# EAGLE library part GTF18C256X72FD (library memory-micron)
2GB (x72, DR) 240-Pin DDR2 SDRAM FBDIMM 1.5V DDR2 SDRAM FBDIMM, MT18GTF25672FDY - 2GB Source: Micron Technology , GTF18C256x72FD.pdf Auto generated by make-symbol-device-package-bsdl.ulp Rev. 20

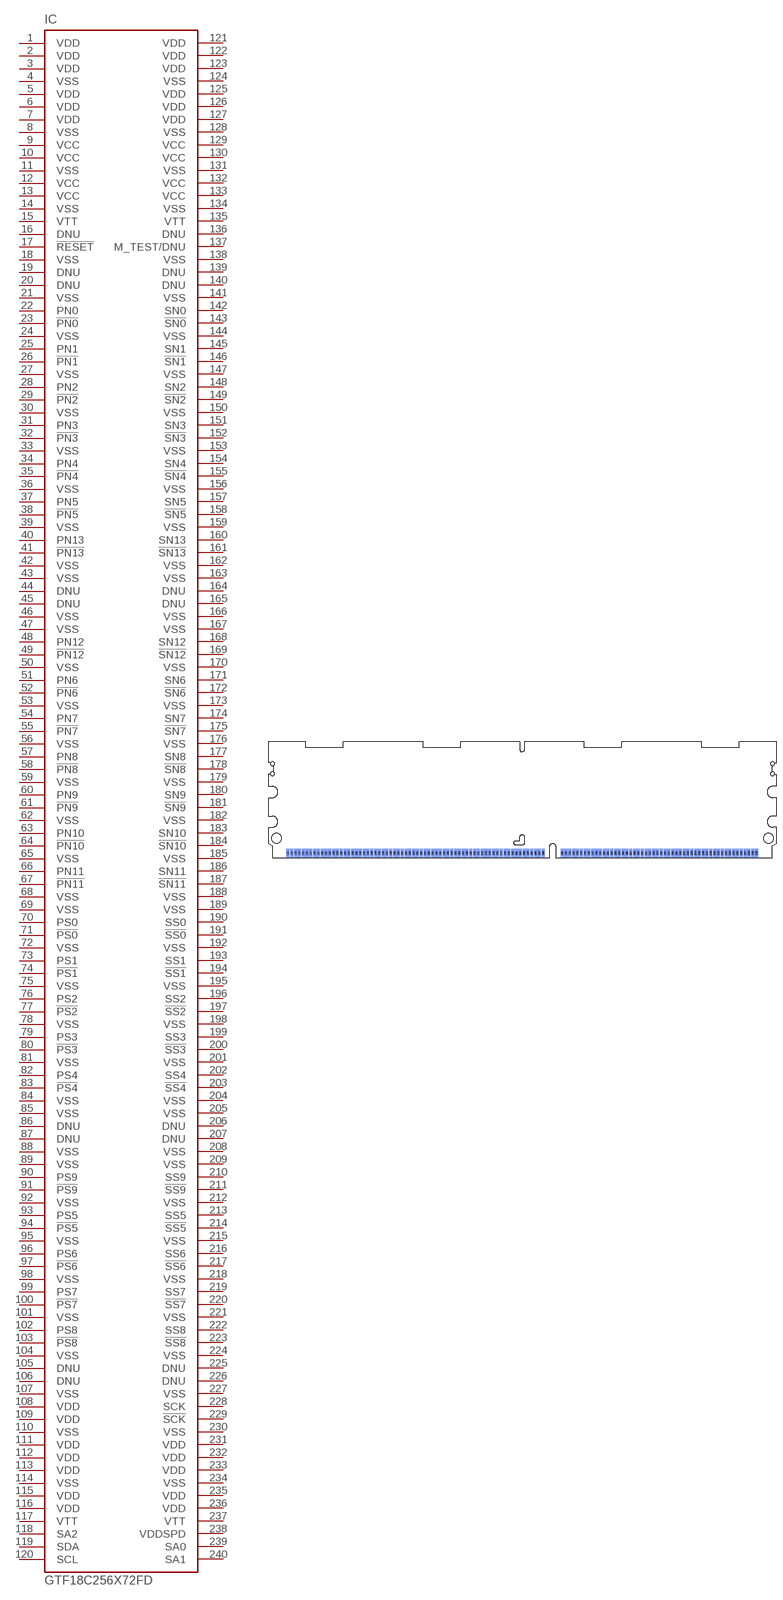
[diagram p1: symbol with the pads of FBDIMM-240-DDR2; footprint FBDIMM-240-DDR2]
Designator prefix IC

## GTF18C256X72FDDIMII-240 (OC_FARNELL: unknown; OC_NEWARK: unknown)  [FBDIMM-240-DDR2]
1  VDD  pas
2  VDD  pas
3  VDD  pas
4  VSS  pas
5  VDD  pas
6  VDD  pas
7  VDD  pas
8  VSS  pas
9  VCC  pas
10  VCC  pas
11  VSS  pas
12  VCC  pas
13  VCC  pas
14  VSS  pas
15  VTT  pas
16  DNU  pas
17  !RESET  pas
18  VSS  pas
19  DNU  pas
20  DNU  pas
21  VSS  pas
22  PN0  pas
23  !PN0  pas
24  VSS  pas
25  PN1  pas
26  !PN1  pas
27  VSS  pas
28  PN2  pas
29  !PN2  pas
30  VSS  pas
31  PN3  pas
32  !PN3  pas
33  VSS  pas
34  PN4  pas
35  !PN4  pas
36  VSS  pas
37  PN5  pas
38  !PN5  pas
39  VSS  pas
40  PN13  pas
41  !PN13  pas
42  VSS  pas
43  VSS  pas
44  DNU  pas
45  DNU  pas
46  VSS  pas
47  VSS  pas
48  PN12  pas
49  !PN12  pas
50  VSS  pas
51  PN6  pas
52  !PN6  pas
53  VSS  pas
54  PN7  pas
55  !PN7  pas
56  VSS  pas
57  PN8  pas
58  !PN8  pas
59  VSS  pas
60  PN9  pas
61  !PN9  pas
62  VSS  pas
63  PN10  pas
64  !PN10  pas
65  VSS  pas
66  PN11  pas
67  !PN11  pas
68  VSS  pas
69  VSS  pas
70  PS0  pas
71  !PS0  pas
72  VSS  pas
73  PS1  pas
74  !PS1  pas
75  VSS  pas
76  PS2  pas
77  !PS2  pas
78  VSS  pas
79  PS3  pas
80  !PS3  pas
81  VSS  pas
82  PS4  pas
83  !PS4  pas
84  VSS  pas
85  VSS  pas
86  DNU  pas
87  DNU  pas
88  VSS  pas
89  VSS  pas
90  PS9  pas
91  !PS9  pas
92  VSS  pas
93  PS5  pas
94  !PS5  pas
95  VSS  pas
96  PS6  pas
97  !PS6  pas
98  VSS  pas
99  PS7  pas
100  !PS7  pas
101  VSS  pas
102  PS8  pas
103  !PS8  pas
104  VSS  pas
105  DNU  pas
106  DNU  pas
107  VSS  pas
108  VDD  pas
109  VDD  pas
110  VSS  pas
111  VDD  pas
112  VDD  pas
113  VDD  pas
114  VSS  pas
115  VDD  pas
116  VDD  pas
117  VTT  pas
118  SA2  pas
119  SDA  pas
120  SCL  pas
121  VDD  pas
122  VDD  pas
123  VDD  pas
124  VSS  pas
125  VDD  pas
126  VDD  pas
127  VDD  pas
128  VSS  pas
129  VCC  pas
130  VCC  pas
131  VSS  pas
132  VCC  pas
133  VCC  pas
134  VSS  pas
135  VTT  pas
136  DNU  pas
137  M_TEST/DNU  pas
138  VSS  pas
139  DNU  pas
140  DNU  pas
141  VSS  pas
142  SN0  pas
143  !SN0  pas
144  VSS  pas
145  SN1  pas
146  !SN1  pas
147  VSS  pas
148  SN2  pas
149  !SN2  pas
150  VSS  pas
151  SN3  pas
152  !SN3  pas
153  VSS  pas
154  SN4  pas
155  !SN4  pas
156  VSS  pas
157  SN5  pas
158  !SN5  pas
159  VSS  pas
160  SN13  pas
161  !SN13  pas
162  VSS  pas
163  VSS  pas
164  DNU  pas
165  DNU  pas
166  VSS  pas
167  VSS  pas
168  SN12  pas
169  !SN12  pas
170  VSS  pas
171  SN6  pas
172  !SN6  pas
173  VSS  pas
174  SN7  pas
175  !SN7  pas
176  VSS  pas
177  SN8  pas
178  !SN8  pas
179  VSS  pas
180  SN9  pas
181  !SN9  pas
182  VSS  pas
183  SN10  pas
184  !SN10  pas
185  VSS  pas
186  SN11  pas
187  !SN11  pas
188  VSS  pas
189  VSS  pas
190  SS0  pas
191  !SS0  pas
192  VSS  pas
193  SS1  pas
194  !SS1  pas
195  VSS  pas
196  SS2  pas
197  !SS2  pas
198  VSS  pas
199  SS3  pas
200  !SS3  pas
201  VSS  pas
202  SS4  pas
203  !SS4  pas
204  VSS  pas
205  VSS  pas
206  DNU  pas
207  DNU  pas
208  VSS  pas
209  VSS  pas
210  SS9  pas
211  !SS9  pas
212  VSS  pas
213  SS5  pas
214  !SS5  pas
215  VSS  pas
216  SS6  pas
217  !SS6  pas
218  VSS  pas
219  SS7  pas
220  !SS7  pas
221  VSS  pas
222  SS8  pas
223  !SS8  pas
224  VSS  pas
225  DNU  pas
226  DNU  pas
227  VSS  pas
228  SCK  pas
229  !SCK  pas
230  VSS  pas
231  VDD  pas
232  VDD  pas
233  VDD  pas
234  VSS  pas
235  VDD  pas
236  VDD  pas
237  VTT  pas
238  VDDSPD  pas
239  SA0  pas
240  SA1  pas

## Footprint FBDIMM-240-DDR2 (pad centres in mm)
240-Pin DDR2 SDRAM FBDIMM (MO-256 R/C B) Source: www.micron.com .. GTF18C256x72FD.pdf
smd 0.8 x 2.3: 1 -69.5,1.25; 2 -68.5,1.25; 3 -67.5,1.25; 4 -66.5,1.25; 5 -65.5,1.25; 6 -64.5,1.25; 7 -63.5,1.25; 8 -62.5,1.25; 9 -61.5,1.25; 10 -60.5,1.25; 11 -59.5,1.25; 12 -58.5,1.25; 13 -57.5,1.25; 14 -56.5,1.25; 15 -55.5,1.25; 16 -54.5,1.25; 17 -53.5,1.25; 18 -52.5,1.25; 19 -51.5,1.25; 20 -50.5,1.25; 21 -49.5,1.25; 22 -48.5,1.25; 23 -47.5,1.25; 24 -46.5,1.25; 25 -45.5,1.25; 26 -44.5,1.25; 27 -43.5,1.25; 28 -42.5,1.25; 29 -41.5,1.25; 30 -40.5,1.25; 31 -39.5,1.25; 32 -38.5,1.25; 33 -37.5,1.25; 34 -36.5,1.25; 35 -35.5,1.25; 36 -34.5,1.25; 37 -33.5,1.25; 38 -32.5,1.25; 39 -31.5,1.25; 40 -30.5,1.25; 41 -29.5,1.25; 42 -28.5,1.25; 43 -27.5,1.25; 44 -26.5,1.25; 45 -25.5,1.25; 46 -24.5,1.25; 47 -23.5,1.25; 48 -22.5,1.25; 49 -21.5,1.25; 50 -20.5,1.25; 51 -19.5,1.25; 52 -18.5,1.25; 53 -17.5,1.25; 54 -16.5,1.25; 55 -15.5,1.25; 56 -14.5,1.25; 57 -13.5,1.25; 58 -12.5,1.25; 59 -11.5,1.25; 60 -10.5,1.25; 61 -9.5,1.25; 62 -8.5,1.25; 63 -7.5,1.25; 64 -6.5,1.25; 65 -5.5,1.25; 66 -4.5,1.25; 67 -3.5,1.25; 68 -2.5,1.25; 69 2.5,1.25; 70 3.5,1.25; 71 4.5,1.25; 72 5.5,1.25; 73 6.5,1.25; 74 7.5,1.25; 75 8.5,1.25; 76 9.5,1.25; 77 10.5,1.25; 78 11.5,1.25; 79 12.5,1.25; 80 13.5,1.25; 81 14.5,1.25; 82 15.5,1.25; 83 16.5,1.25; 84 17.5,1.25; 85 18.5,1.25; 86 19.5,1.25; 87 20.5,1.25; 88 21.5,1.25; 89 22.5,1.25; 90 23.5,1.25; 91 24.5,1.25; 92 25.5,1.25; 93 26.5,1.25; 94 27.5,1.25; 95 28.5,1.25; 96 29.5,1.25; 97 30.5,1.25; 98 31.5,1.25; 99 32.5,1.25; 100 33.5,1.25; 101 34.5,1.25; 102 35.5,1.25; 103 36.5,1.25; 104 37.5,1.25; 105 38.5,1.25; 106 39.5,1.25; 107 40.5,1.25; 108 41.5,1.25; 109 42.5,1.25; 110 43.5,1.25; 111 44.5,1.25; 112 45.5,1.25; 113 46.5,1.25; 114 47.5,1.25; 115 48.5,1.25; 116 49.5,1.25; 117 50.5,1.25; 118 51.5,1.25; 119 52.5,1.25; 120 53.5,1.25
smd 0.8 x 2.3 bottom: 121 -69.5,1.25; 122 -68.5,1.25; 123 -67.5,1.25; 124 -66.5,1.25; 125 -65.5,1.25; 126 -64.5,1.25; 127 -63.5,1.25; 128 -62.5,1.25; 129 -61.5,1.25; 130 -60.5,1.25; 131 -59.5,1.25; 132 -58.5,1.25; 133 -57.5,1.25; 134 -56.5,1.25; 135 -55.5,1.25; 136 -54.5,1.25; 137 -53.5,1.25; 138 -52.5,1.25; 139 -51.5,1.25; 140 -50.5,1.25; 141 -49.5,1.25; 142 -48.5,1.25; 143 -47.5,1.25; 144 -46.5,1.25; 145 -45.5,1.25; 146 -44.5,1.25; 147 -43.5,1.25; 148 -42.5,1.25; 149 -41.5,1.25; 150 -40.5,1.25; 151 -39.5,1.25; 152 -38.5,1.25; 153 -37.5,1.25; 154 -36.5,1.25; 155 -35.5,1.25; 156 -34.5,1.25; 157 -33.5,1.25; 158 -32.5,1.25; 159 -31.5,1.25; 160 -30.5,1.25; 161 -29.5,1.25; 162 -28.5,1.25; 163 -27.5,1.25; 164 -26.5,1.25; 165 -25.5,1.25; 166 -24.5,1.25; 167 -23.5,1.25; 168 -22.5,1.25; 169 -21.5,1.25; 170 -20.5,1.25; 171 -19.5,1.25; 172 -18.5,1.25; 173 -17.5,1.25; 174 -16.5,1.25; 175 -15.5,1.25; 176 -14.5,1.25; 177 -13.5,1.25; 178 -12.5,1.25; 179 -11.5,1.25; 180 -10.5,1.25; 181 -9.5,1.25; 182 -8.5,1.25; 183 -7.5,1.25; 184 -6.5,1.25; 185 -5.5,1.25; 186 -4.5,1.25; 187 -3.5,1.25; 188 -2.5,1.25; 189 2.5,1.25; 190 3.5,1.25; 191 4.5,1.25; 192 5.5,1.25; 193 6.5,1.25; 194 7.5,1.25; 195 8.5,1.25; 196 9.5,1.25; 197 10.5,1.25; 198 11.5,1.25; 199 12.5,1.25; 200 13.5,1.25; 201 14.5,1.25; 202 15.5,1.25; 203 16.5,1.25; 204 17.5,1.25; 205 18.5,1.25; 206 19.5,1.25; 207 20.5,1.25; 208 21.5,1.25; 209 22.5,1.25; 210 23.5,1.25; 211 24.5,1.25; 212 25.5,1.25; 213 26.5,1.25; 214 27.5,1.25; 215 28.5,1.25; 216 29.5,1.25; 217 30.5,1.25; 218 31.5,1.25; 219 32.5,1.25; 220 33.5,1.25; 221 34.5,1.25; 222 35.5,1.25; 223 36.5,1.25; 224 37.5,1.25; 225 38.5,1.25; 226 39.5,1.25; 227 40.5,1.25; 228 41.5,1.25; 229 42.5,1.25; 230 43.5,1.25; 231 44.5,1.25; 232 45.5,1.25; 233 46.5,1.25; 234 47.5,1.25; 235 48.5,1.25; 236 49.5,1.25; 237 50.5,1.25; 238 51.5,1.25; 239 52.5,1.25; 240 53.5,1.25
hole 2.6 at -72.495,5.2
hole 2.6 at 56.645,5.2
hole 1 at -73.565,24.75
hole 1 at -73.57,22.075
hole 1 at 57.69,24.75
hole 1 at 57.695,22.075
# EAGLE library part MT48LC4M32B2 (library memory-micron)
SYNCHRONOUS DRAM 1 Meg x 32 x 4 banks Source: http://www.datasheetcatalog.org/datasheet/micron/MT48LC4M32B2.pdf

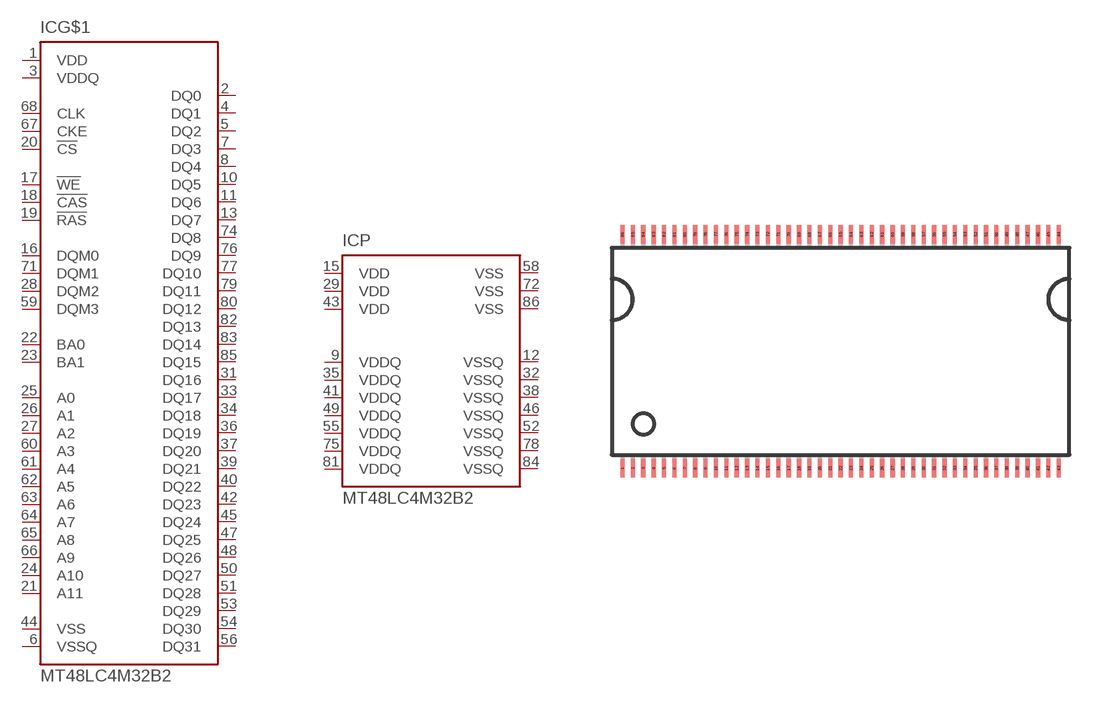
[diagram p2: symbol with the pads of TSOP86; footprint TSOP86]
Designator prefix IC; gates G$1=MT48LC4M32B2 P=MT48LC4M32B2-PWR

## MT48LC4M32B2 (MPN: MT48LC4M32B2P-6:G; OC_FARNELL: 1216286; OC_NEWARK: 97K6124)  [TSOP86]
1  G$1:VDD  pwr
2  G$1:DQ0  in
3  G$1:VDDQ  pwr
4  G$1:DQ1  in
5  G$1:DQ2  in
6  G$1:VSSQ  pwr
7  G$1:DQ3  in
8  G$1:DQ4  in
9  P:VDDQ  pwr
10  G$1:DQ5  in
11  G$1:DQ6  in
12  P:VSSQ  pwr
13  G$1:DQ7  in
15  P:VDD  pwr
16  G$1:DQM0  in
17  G$1:!WE  in
18  G$1:!CAS  in
19  G$1:!RAS  in
20  G$1:!CS  in
21  G$1:A11  in
22  G$1:BA0  in
23  G$1:BA1  in
24  G$1:A10  in
25  G$1:A0  in
26  G$1:A1  in
27  G$1:A2  in
28  G$1:DQM2  in
29  P:VDD  pwr
31  G$1:DQ16  in
32  P:VSSQ  pwr
33  G$1:DQ17  in
34  G$1:DQ18  in
35  P:VDDQ  pwr
36  G$1:DQ19  in
37  G$1:DQ20  in
38  P:VSSQ  pwr
39  G$1:DQ21  in
40  G$1:DQ22  in
41  P:VDDQ  pwr
42  G$1:DQ23  in
43  P:VDD  pwr
44  G$1:VSS  pwr
45  G$1:DQ24  in
46  P:VSSQ  pwr
47  G$1:DQ25  in
48  G$1:DQ26  in
49  P:VDDQ  pwr
50  G$1:DQ27  in
51  G$1:DQ28  in
52  P:VSSQ  pwr
53  G$1:DQ29  in
54  G$1:DQ30  in
55  P:VDDQ  pwr
56  G$1:DQ31  in
58  P:VSS  pwr
59  G$1:DQM3  in
60  G$1:A3  in
61  G$1:A4  in
62  G$1:A5  in
63  G$1:A6  in
64  G$1:A7  in
65  G$1:A8  in
66  G$1:A9  in
67  G$1:CKE  in
68  G$1:CLK  in
71  G$1:DQM1  in
72  P:VSS  pwr
74  G$1:DQ8  in
75  P:VDDQ  pwr
76  G$1:DQ9  in
77  G$1:DQ10  in
78  P:VSSQ  pwr
79  G$1:DQ11  in
80  G$1:DQ12  in
81  P:VDDQ  pwr
82  G$1:DQ13  in
83  G$1:DQ14  in
84  P:VSSQ  pwr
85  G$1:DQ15  in
86  P:VSS  pwr

## Footprint TSOP86 (pad centres in mm)
TSOP86 Auto generated by make-symbol-device-package-bsdl.ulp Rev. 26
smd 0.2 x 0.9: 1 -10.5,-5.63; 2 -10,-5.63; 3 -9.5,-5.63; 4 -9,-5.63; 5 -8.5,-5.63; 6 -8,-5.63; 7 -7.5,-5.63; 8 -7,-5.63; 9 -6.5,-5.63; 10 -6,-5.63; 11 -5.5,-5.63; 12 -5,-5.63; 13 -4.5,-5.63; 14 -4,-5.63; 15 -3.5,-5.63; 16 -3,-5.63; 17 -2.5,-5.63; 18 -2,-5.63; 19 -1.5,-5.63; 20 -1,-5.63; 21 -0.5,-5.63; 22 0,-5.63; 23 0.5,-5.63; 24 1,-5.63; 25 1.5,-5.63; 26 2,-5.63; 27 2.5,-5.63; 28 3,-5.63; 29 3.5,-5.63; 30 4,-5.63; 31 4.5,-5.63; 32 5,-5.63; 33 5.5,-5.63; 34 6,-5.63; 35 6.5,-5.63; 36 7,-5.63; 37 7.5,-5.63; 38 8,-5.63; 39 8.5,-5.63; 40 9,-5.63; 41 9.5,-5.63; 42 10,-5.63; 43 10.5,-5.63; 44 10.5,5.63; 45 10,5.63; 46 9.5,5.63; 47 9,5.63; 48 8.5,5.63; 49 8,5.63; 50 7.5,5.63; 51 7,5.63; 52 6.5,5.63; 53 6,5.63; 54 5.5,5.63; 55 5,5.63; 56 4.5,5.63; 57 4,5.63; 58 3.5,5.63; 59 3,5.63; 60 2.5,5.63; 61 2,5.63; 62 1.5,5.63; 63 1,5.63; 64 0.5,5.63; 65 0,5.63; 66 -0.5,5.63; 67 -1,5.63; 68 -1.5,5.63; 69 -2,5.63; 70 -2.5,5.63; 71 -3,5.63; 72 -3.5,5.63; 73 -4,5.63; 74 -4.5,5.63; 75 -5,5.63; 76 -5.5,5.63; 77 -6,5.63; 78 -6.5,5.63; 79 -7,5.63; 80 -7.5,5.63; 81 -8,5.63; 82 -8.5,5.63; 83 -9,5.63; 84 -9.5,5.63; 85 -10,5.63; 86 -10.5,5.63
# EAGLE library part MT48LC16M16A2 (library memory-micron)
256Mb: x16 SDRAM MT48LC16M16A2 - 4 Meg x 16 x 4 banks Source: http://download.micron.com/pdf/datasheets/dram/sdram/256MSDRAM.pdf

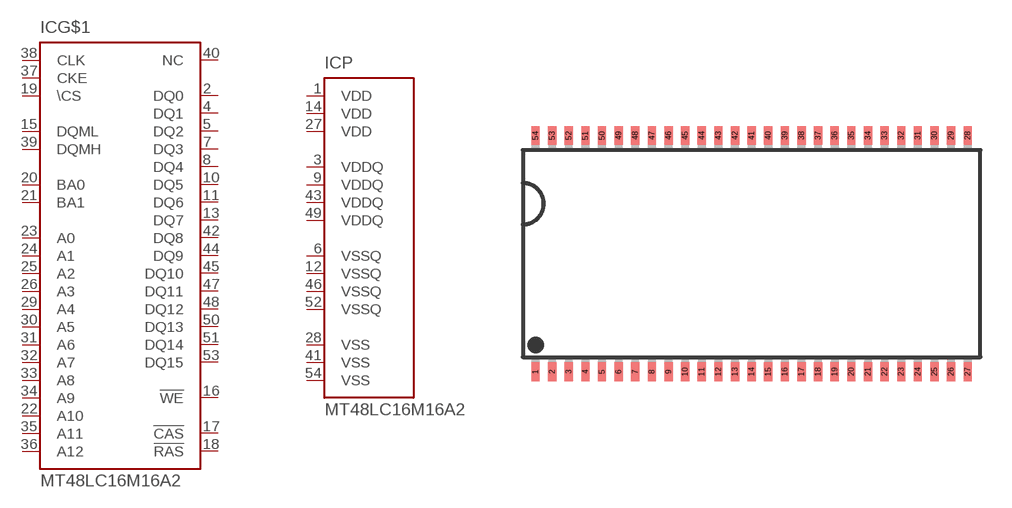
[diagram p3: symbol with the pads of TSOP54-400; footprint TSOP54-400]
Designator prefix IC; gates P=MT48LC64/32/16M-PWR G$1=MT48LC64M444A2

## MT48LC16M16A2 (OC_FARNELL: unknown; OC_NEWARK: unknown)  [TSOP54-400]
1  P:VDD  pwr
2  G$1:DQ0  hiz
3  P:VDDQ  pwr
4  G$1:DQ1  hiz
5  G$1:DQ2  hiz
6  P:VSSQ  pwr
7  G$1:DQ3  hiz
8  G$1:DQ4  hiz
9  P:VDDQ  pwr
10  G$1:DQ5  hiz
11  G$1:DQ6  hiz
12  P:VSSQ  pwr
13  G$1:DQ7  hiz
14  P:VDD  pwr
15  G$1:DQML  in
16  G$1:!WE  in
17  G$1:!CAS  in
18  G$1:!RAS  in
19  G$1:\CS  in
20  G$1:BA0  in
21  G$1:BA1  in
22  G$1:A10  in
23  G$1:A0  in
24  G$1:A1  in
25  G$1:A2  in
26  G$1:A3  in
27  P:VDD  pwr
28  P:VSS  pwr
29  G$1:A4  in
30  G$1:A5  in
31  G$1:A6  in
32  G$1:A7  in
33  G$1:A8  in
34  G$1:A9  in
35  G$1:A11  in
36  G$1:A12  in
37  G$1:CKE  in
38  G$1:CLK  in
39  G$1:DQMH  in
40  G$1:NC  nc
41  P:VSS  pwr
42  G$1:DQ8  hiz
43  P:VDDQ  pwr
44  G$1:DQ9  hiz
45  G$1:DQ10  hiz
46  P:VSSQ  pwr
47  G$1:DQ11  hiz
48  G$1:DQ12  hiz
49  P:VDDQ  pwr
50  G$1:DQ13  hiz
51  G$1:DQ14  hiz
52  P:VSSQ  pwr
53  G$1:DQ15  hiz
54  P:VSS  pwr

## Footprint TSOP54-400 (pad centres in mm)
54-Pin Plastic TSOP (400 mil) Source: http://download.micron.com/pdf/datasheets/dram/sdram/256MSDRAM.pdf
smd 0.4 x 0.9: 1 -10.4,-5.68; 2 -9.6,-5.68; 3 -8.8,-5.68; 4 -8,-5.68; 5 -7.2,-5.68; 6 -6.4,-5.68; 7 -5.6,-5.68; 8 -4.8,-5.68; 9 -4,-5.68; 10 -3.2,-5.68; 11 -2.4,-5.68; 12 -1.6,-5.68; 13 -0.8,-5.68; 14 0,-5.68; 15 0.8,-5.68; 16 1.6,-5.68; 17 2.4,-5.68; 18 3.2,-5.68; 19 4,-5.68; 20 4.8,-5.68; 21 5.6,-5.68; 22 6.4,-5.68; 23 7.2,-5.68; 24 8,-5.68; 25 8.8,-5.68; 26 9.6,-5.68; 27 10.4,-5.68; 28 10.4,5.68; 29 9.6,5.68; 30 8.8,5.68; 31 8,5.68; 32 7.2,5.68; 33 6.4,5.68; 34 5.6,5.68; 35 4.8,5.68; 36 4,5.68; 37 3.2,5.68; 38 2.4,5.68; 39 1.6,5.68; 40 0.8,5.68; 41 0,5.68; 42 -0.8,5.68; 43 -1.6,5.68; 44 -2.4,5.68; 45 -3.2,5.68; 46 -4,5.68; 47 -4.8,5.68; 48 -5.6,5.68; 49 -6.4,5.68; 50 -7.2,5.68; 51 -8,5.68; 52 -8.8,5.68; 53 -9.6,5.68; 54 -10.4,5.68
